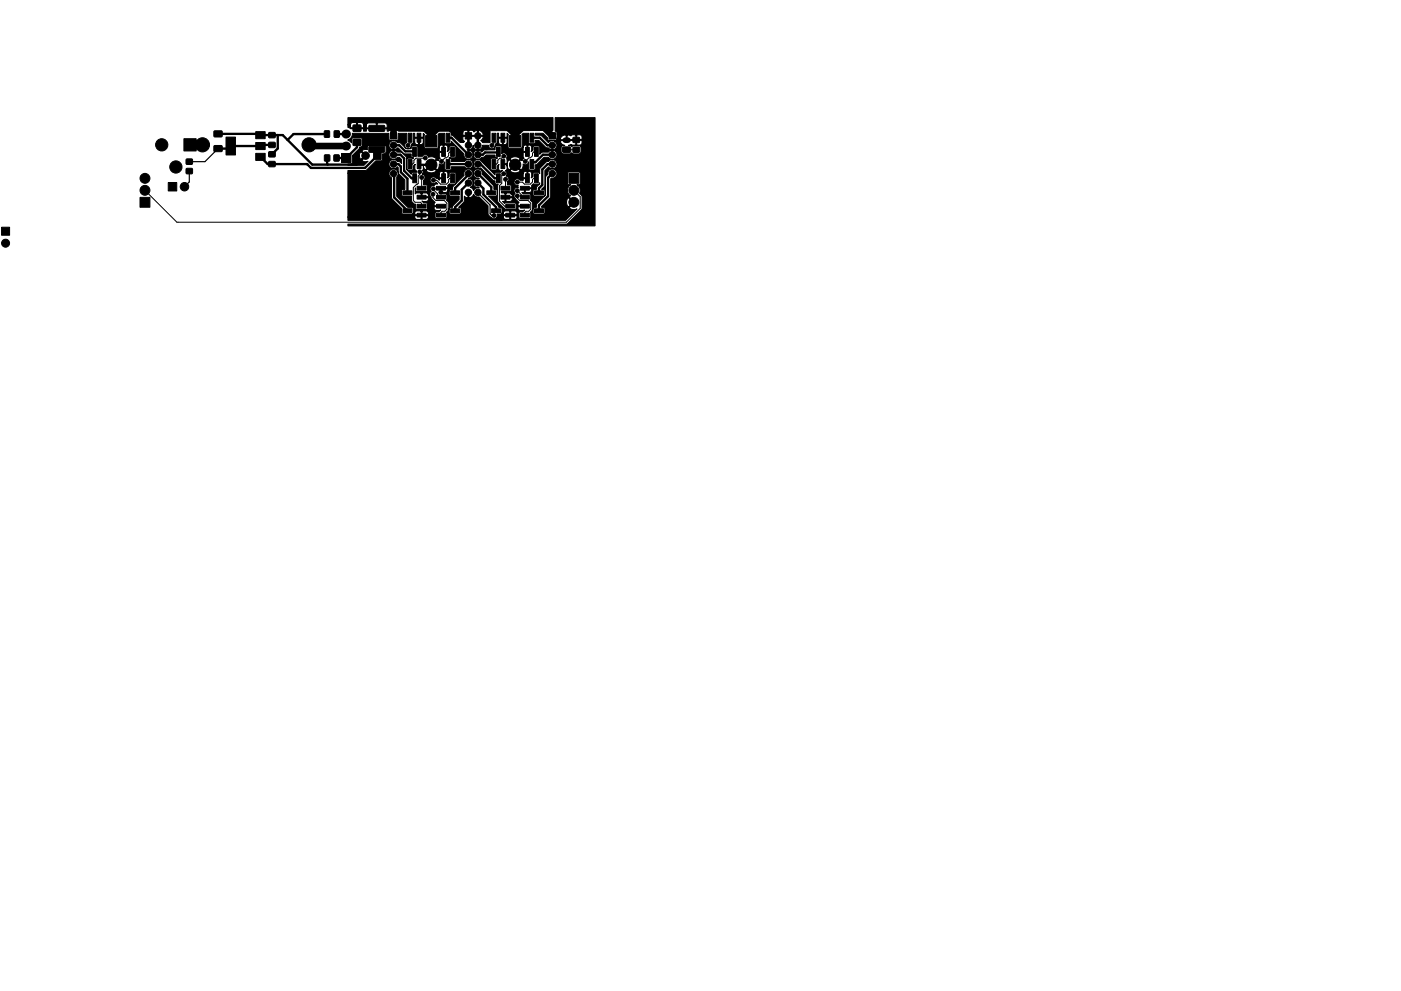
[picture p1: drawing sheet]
<svg xmlns="http://www.w3.org/2000/svg" width="297mm" height="210mm" viewBox="0 0 297 210" stroke-linecap="round" stroke-linejoin="round" font-family="sans-serif">
<g fill="#000" stroke="#000" stroke-width=".21">
<path d="M39 29.4h2.6v2.6h-2.6zM39.5 35.8h1.2l.1 1h-1.3zM39.5 33.8h1.2l.1 1h-1.3zM45.4 27.8h1.6l.1 1.2h-1.7zM45.4 30.9h1.6l.1 1.2h-1.7zM47.9 29.1h2v3.8h-2zM54.2 27.9h2v1.5h-2zM54.2 32.5h2v1.5h-2zM54.2 30.2h2v1.5h-2zM57 28.2l1.3-.1v1.1h-1.3zM57 30.2h1.3v1l-1.3 .1zM57 32.2h1.3v1l-1.3 .1z"/>
<path d="M57 34.3h1.3v1h-1.3zM68.8 27.8h1.1l-.1 1.3h-1zM68.8 32.9h1.1v1.3l-1.1-.1zM70.8 32.9h1.1v1.3l-1.1-.1zM70.9 27.8h1v1.3h-1zM72.4 32.6h2v1.9h-2zM74.9 29.5h1.6v1.3h-1.6zM74.9 26.6h1.6v1.2l-1.6 .1zM79.2 32.2h1.6v1.6h-1.6zM78.3 26.7l3.1-.1 .2 .2v.9l-.3 .2h-2.9l-.2-.2zM78.3 31.1l3.1-.1 .2 .2v1l-.3 .1h-2.9l-.2-.2zM82.8 28.1h1.3v1.4h-1.3z"/>
<path d="M86.5 28.3h.8v1.9h-.8zM86.6 33.9h.8v1.9h-.8zM87.5 31.3h.8v1.9h-.8zM87.5 36.9h.8v1.9h-.8zM88.4 28.3h.8v1.9h-.8zM88.5 33.9h.8v1.9h-.8zM88.8 34.7h.2v.2h-.3zM90.2 28.8h2.4v2.4h-2.4zM88.4 39.5h1.9v.8h-1.9zM93.6 31.3h.8v1.9h-.8zM93.6 36.9h.8v1.9h-.8zM94.6 28.3h.8v1.9h-.8z"/>
<path d="M94.6 33.9h.8v1.9h-.8zM95.5 31.3h.8v1.9h-.8zM95.5 36.9h.8v1.9h-.8zM98.6 28.1h1.4v1.4h-1.4zM104.3 28.3h.8v1.9h-.8zM104.3 33.9h.8v1.9h-.8zM105.3 31.3h.8v1.9h-.8zM105.3 36.9h.8v1.9h-.8zM106.2 28.3h.8v1.9h-.8zM106.2 33.9h.8v1.9h-.8zM108 28.8h2.4v2.4h-2.4zM106.2 39.5h1.9v.8h-1.9z"/>
<path d="M111.4 31.3h.8v1.9h-.8zM111.4 36.9h.8v1.9h-.8zM112.4 28.3h.8v1.9h-.8zM112.4 33.9h.8v1.9h-.8zM113.3 31.3h.8v1.9h-.8zM113.3 36.9h.8v1.9h-.8zM73.8 25h43.4v2.7h-13.2l-.1 2.6h-1.6l-.4-.5 .4-.4 .2-.3-.1-.2h-1v1.4h-.2v-1.4h-1.8v1.3h-.2v-1.3h-.9l-.2 .7 .4 .4-.2 .2h-.7l-1.5-1.4-.4-.1v-.6h2.4l.2 .6h.9v-.9h.2v.9h1.8v-.9h.2v.9h1a.85 .85 0 0 0-1.2-.9l-.2-.1-.5 .3-.4-.3-.9 .1-.6-.2-.3 .2-.2 .3h-2.4l-.5-.3h-10.7l-.4-.2h-.4l-.2 .2-.7-.2-.7 .2-.1-.5h-4.2l-.1 .5h-.6l-.2-.5-2.5 .1-.6-.4v-.5h.5l.1 .6h1.2v-1h.2v1h1.1l.2-.5h.6l.1 .5h2v-.9h.2v.9h2l.1-.6-.4-.4-1.9 .1-.1-.1h-1.5l-.4 .1-.1 .4h-.6l-.1-.4-.3-.2-1.1 .1-.8-.1-.3 .1-.2 .4h-.5zM116.4 28.1h1.4v1.4h-1.4zM120.6 36.8h2.1v2.1h-2.1zM119.3 31.2h1.6l.1 1-1.6 .1zM121.5 31.3l1.3-.1v1.1h-1.3zM121.5 29.2h1.3v1h-1.3z"/>
<path d="M.3 48.2h1.7v1.7h-1.7zM29.7 41.9h2.1v2.1h-2.1zM35.7 38.7h1.8v1.8h-1.8zM85.4 44.3h1.9v.8h-1.9zM85.4 40.5h1.9v.8h-1.9zM88.4 45.2h1.9v.8h-1.9zM88.4 43.3h1.9v.8h-1.9zM88.4 41.4h1.9v.8h-1.9zM92.5 43.3h1.9v.8h-1.9zM92.5 45.2h1.9v.8h-1.9zM92.5 39.5h1.9v.8h-1.9zM92.5 41.4h1.9v.8h-1.9z"/>
<path d="M95.5 44.3h1.9v.8h-1.9zM95.5 40.5h1.9v.8h-1.9zM103.2 40.5h1.9v.8h-1.9zM104.2 44.3h1.9v.8h-1.9zM106.2 41.4h1.9v.8h-1.9zM107.2 45.2h1.9v.8h-1.9zM107.2 43.3h1.9v.8h-1.9zM110.3 43.3h1.9v.8h-1.9zM110.3 45.2h1.9v.8h-1.9zM110.3 39.5h1.9v.8h-1.9zM110.3 41.4h1.9v.8h-1.9zM113.3 44.3h1.9v.8h-1.9z"/>
<path d="M113.3 40.5h1.9v.8h-1.9zM74.7 28.3h7.7l.1 1.4 .9 .1 1-.1v-1.4h1.8v1.9a.71 .71 0 0 0-.3 .9 .71 .71 0 0 0 .8 .4 .71 .71 0 0 0 .5-.8l.4-.5h.3l.1 .2a.48 .48 0 0 0 .7 .2v-1.3h.2v1.3l.2 .1a.54 .54 0 0 0 .6-.5l-.1-.9h-1.5l-.2 .9h-.3v-1.9h.3l.2 .8h1.5l.1-.8 .3 .3-.1 2.6 .2 .2 2.5 .1 .5-.2v.7l.8 .1v-1.2l-.1-.1a.54 .54 0 0 0-.7 .5h-.2v-2.7l.2-.3h1.2l.1 2.1 1.1 .1 .2-.5 2.7 2.6a.98 .98 0 0 0 .9 1.2 .98 .98 0 0 0 1-1.1 1.1 1.1 0 0 0 .9 1.1l.6-.1 .3-.3 .5-.1 .5-.4h1.9l.1 .5 .4 .1-.2 .2-1-.1-.2 .1-.1 2.1 .3 .3 .9-.1 .2-.2v-.6l.4-.3-.1 .1v1a.48 .48 0 0 0 .8 .1l-.4 .5h-1l-.1 .5-2.7-2.7a.99 .99 0 0 0-1.4-.5 .99 .99 0 0 0-.4 1.4 .99 .99 0 0 0 1.4 .3l2.6 2.6 .5 .2 .1 .6 .5 .1-.1 .3v3.3l.1 .2 1.5 1.5h2.2l.1-.3-.1-1-2.1-.1-.2 .2-.4-.5 .5-.1v-.7h.2l.1 .8h.9a.48 .48 0 0 0 .2-.8h-1.5l.1-.8h.2v.6h1.2l.1-.1a.54 .54 0 0 0-.5-.7l-1 .2-.8-.2v-.3h2l.1-.2v-1l-.2-.2h-.6v-.6h1.4v.1a.7 .7 0 0 0 .9 .6v.5a.7 .7 0 0 0-.8 .3 .7 .7 0 0 0 .1 .9 .84 .84 0 0 0 .2 1.3l.7 .6-.3 .4 .2 .3h1.4v.3l-1.4-.1a.48 .48 0 0 0-.1 .6 .48 .48 0 0 0 .4 .3l.9-.2-.3 .4-.8 .2v1.2h2.2l.2-.2-.1-1.1 .5-.4v-.3l.1 .9 .2 .2 2.2-.1 .1-1.1-.2-.2h-.5v-.2l.9-.8h4.4a.88 .88 0 0 0 .5 .9l.9-1-.9-.9a.96 .96 0 0 0-.5 1h-4.4l1-1.3 .1-3.8 .2-.1a.98 .98 0 0 0 1.1-1 .98 .98 0 0 0-1.1-.9 .98 .98 0 0 0-.9 1.1l-.4 .6v3.8l-1.9 1.8-.1 .8h-.5l-.2 .3-.1-1.3-.5-.5 .1-1.2-.3-.2h-1.3l-.3-.3 .6-.1v-.7h.2l.1 .8h.8a.48 .48 0 0 0 .3-.8h-1.4v-.2h1.4l.1-.4 .4-.4 1.1 .1 .2-.3v.2l-.6 .7-.1 .5h-.4l-.3 .2v1l.3 .2h1.9l.3-.1v-1.1l-.2-.2h-.5l.7-.9v-3.1l.8-.8a.98 .98 0 0 0 1.5 .1 .98 .98 0 0 0-.1-1.4 .98 .98 0 0 0-1.4 .2l-.5 .1-1.3 1.2-.1 1.3-.2-.3h-1l-.2 .2v.6l-.4 .3 .1-.1v-.8a.48 .48 0 0 0-.8-.3v1.4h-.8l-.2 .4-.6-.1a.7 .7 0 0 0-.8-.2 .7 .7 0 0 0-.5 .6h-1.4l.1-.1a.7 .7 0 0 0-.4-1.1l.2-.5h3.4v.7l.8 .1v-1.2a.48 .48 0 0 0-.5-.1 .48 .48 0 0 0-.3 .5h-3.4l-.4-.7h.2h.9l.4 .4 .7 .1 .6-.2 .4-.3-1.1-1.1-1 1.1h-.9l.2-.3v-.9a1.02 1.02 0 0 0 .5 1l1.1-1h.3l1 1 .4-.4 .1-.8a.7 .7 0 0 0 1.2-.5v1.6l1.1 .2 .3-.3v-.8l.4-.2 1.5-1.4h.9a.98 .98 0 0 0 1.5 .1 .98 .98 0 0 0-.1-1.4 .98 .98 0 0 0-1.4 .2h-1.3l-.6 .4-.1-1.6-1.1-.1-.2 .9-.4 .2 .1-.1v-.8a.48 .48 0 0 0-.8-.3v1.4h-.8l-.2 .9a.43 .43 0 0 1-.1 .7l-.1 .2-.3-.2-1 1.1h-.3l-1.1-1.1-.4 .4-.1 .7-1-.1v-.2h.9l.1-.1v-.8h.7l1 1 1.1-1a1.31 1.31 0 0 0-2.1 0h-.7l-.1-.2a.74 .74 0 0 0-.1-.9 .74 .74 0 0 0-.9-.1v-1.4l-.3-.2h-1l-.1 .8h-2.3l-.6 .5a1.02 1.02 0 0 0-1-.4 1.02 1.02 0 0 0-.8 .8 .97 .97 0 0 0-1.2-.8l-.1-.1a1.04 1.04 0 0 0 1.3-1 .98 .98 0 0 0 1 1 .98 .98 0 0 0 1-1h1.3v.1a.75 .75 0 0 0 .9 .6 .75 .75 0 0 0 .5-.9l.4-.4 .3 .1a.48 .48 0 0 0 .8 .3v-1.3h.2v1.3l.1 .1a.54 .54 0 0 0 .7-.5l-.1-.9h-1.6l-.1 .9h-.3v-1.9h.3l.1 .8h1.6l.1-.8 .3 .3-.1 2.6 .2 .2 2.5 .1 .5-.2v.7l.8 .1v-1.2a.48 .48 0 0 0-.5-.1 .48 .48 0 0 0-.3 .5h-.2l-.1-2.7 .3-.3h1.2v1.9l.1 .2 1.1 .1 .2-.3v-.4h.7l1.5 1.5 .6 .1a.98 .98 0 0 0 1.5 .1 .98 .98 0 0 0-.2-1.5h1.2l.4 .6 .6 .2a.61 .61 0 0 0-.8 .6v.9l.5 .3h1.4l.3-.2 .4 .2h1.3l.3-.4v-.8a.55 .55 0 0 0-.6-.5h-1l-.4 .2-.2-.2-.5-.1 .6-.2 .8 .2 .2-.1v-.9h.2v.9l.1 .1 .7-.1 .3-.3-.1-.6-5.7 .2a1 1 0 0 0-1.3 .3l-1.5-1.5-1.3-.1v-.4h1.6l1 1v.3l.3 .2h1.4l.3-.3 1.9 .1v-1h.2v1h1.9v-.9h.2v.9h1l.1-.1v-.6l-.4-.3-.7 .1-.9-.1-.4 .2-.3-.1a1.44 1.44 0 0 0-1.9 .8h-.7v-1.4l-.4-.3v-2.8h8.5v22.9h-52.4v-.4h46.4l3.2-3.2v-2.6l-.5-.7 .1-.8-.1-.5-.6-.5h.5l.2-.3v-2.1l-.1-.3h-2.3l-.2 .1-.1 2.3 .2 .3h.5a1.35 1.35 0 0 0 0 2.3l-.3 .3 1.1 1.1-1.1 1.1a1.23 1.23 0 0 0 1.6 .3l-2.4 2.4h-46.1v-.7h14.1l.3 .5h1l.1-.8h.2l.1 .8h.8a.48 .48 0 0 0 .3-.8h-2.6l-.2 .3h-14.1v-9.3h8.7l.1 .6 .4 .4 .1 4.4 2 2.1 .1 1.1 2.1 .1 .6-.2 .2 .3h1.2v-.6h.2v.6h1.2a.48 .48 0 0 0 .1-.5 .48 .48 0 0 0-.5-.3l-.8 .2-1.2-.1-.3 .2-.1 .2h-.3l-.1-1.1-1-.1-2.4-2.3 .1-4.3a.98 .98 0 0 0-.4-1.5 .98 .98 0 0 0-1.3 .8h-8.7v-.5l3.9-.1 2-2 1.3-.1 .1-1.4h.2a.55 .55 0 0 0 .6-.5v-.9l-.4-.4-3.1-.1a.55 .55 0 0 0-.5 .6v.5l-.7-.1-.4 .2-.1 .2 1 .9-1 .9 .1 .2 .5 .2 .7-.1-.8 .9h-3.4v-.3h.7l.2-.2v-1.5h1.5l.2 .6 .2 .1 .8-.8-.8-.7h-.2l-.2 .8h-1.5l1.4-1.5 .1-.4 .4-.1 .3-.4h5.6a.98 .98 0 0 0 .6 1 .98 .98 0 0 0 1.1-.3h.2l1.3 1.2 1.5 .1v.6l.5 .2-.1 .1h-1l-.3 .1v2.1l.2 .3 1-.1 .2-.2v-.6l.4-.3-.1 .1v.9l.3 .3v.4h-.9l-.2 .4-1-1-.1-2.7-.9-.9-1-.2a.98 .98 0 0 0-1.4-.1 .98 .98 0 0 0 0 1.5 .98 .98 0 0 0 1.4-.2h.5l.4 .4v.9l-.4-.4h-.5a.98 .98 0 0 0-1.4-.2 .98 .98 0 0 0 0 1.5 .98 .98 0 0 0 1.5-.2l.1 .1 .1 1.3 1.3 1.4v2h-.4l-.2 .2v1.1l2 .1 .1 1.1 .5 .6h.3v.9l.3 .2h2.1l.1-.3v-.9l-.8-.2-.3-.4 .1 .1h.9a.48 .48 0 0 0 .2-.8l-1.4 .1v-.9h.2v.6h1.2l.1-.1-.1-.5h.4l.4 1.1 .8 .7-.3 .6 .2 .1h1.4v.3l-1.4-.1a.48 .48 0 0 0-.1 .6 .48 .48 0 0 0 .4 .3l.9-.2-.3 .4-.8 .2-.1 .9 .2 .3h2l.3-.1v-1.2l.4-.5v-1.5l-.4-.5v-1.3l-1.5-.1-.1-.3 .3-.1v-.7h.2l.1 .8h.8l.4-.3h.3l.1 .8 .1 .3h1.9v.7l-1.2 1.3-.2 .4h-.4l-.2 .2v1l.2 .2 2.2-.1v-1.1l-.5-.2 1.2-1.2v-1.2l.6 .4 .2-.1v-1.2h.2v1.2l.2 .1 .6-.4 .2-.4a.97 .97 0 0 0 1.2 .6l1.9 1.9v1.7l.4 .6a.9 .9 0 0 0 1.5 0h1.3l.3 .5h1l.1-.8h.2l.1 .8h.9a.48 .48 0 0 0 .2-.8h-2.6l-.2 .3h-1.3v-.6l1.3-.2 .2 .3h1.2v-.6h.2v.6h1.2l.1-.1a.54 .54 0 0 0-.5-.7l-.8 .2-1.2-.1-.3 .2-.1 .2h-.3v-1.1l-.7-.1-.1-.4-2-2 1.7-.1 .1-.2v-.9l-.2-.2h-.5l-.1-.8-2.3-2.4a.98 .98 0 0 0-.9-1.2 .98 .98 0 0 0-1.1 1.1 .98 .98 0 0 0 1.2 .9l.1 .1a.98 .98 0 0 0-1.3 .9 .98 .98 0 0 0 1.2 1l.1 .1a.97 .97 0 0 0-1.2 .5l-.2-.4-.5-.3a.97 .97 0 0 0 .6-1.1 .97 .97 0 0 0-1-.8 .99 .99 0 0 0 1-1 .99 .99 0 0 0-1.2-.9 .99 .99 0 0 0-.7 1.3l-2.3 2.3-.2 .7h-.4l-.3 .3h-.3l-.1-.5h-1.4v-.2h1.4l.1-.4 .4-.4 1.1 .1 .2-.3v-2.1l-1.2-.1-.2 .8-.4 .3 .1-.1v-.8a.48 .48 0 0 0-.8-.3v1.4h-.8l-.2 .3-.5-.4a.76 .76 0 0 0-1-.2 .76 .76 0 0 0-.2 1.1 .7 .7 0 0 0 1.1 0l.3 .3-.4 .1-.4 .2a.7 .7 0 0 0-.7 .5 .7 .7 0 0 0 .2 .8l-.4 .5-.8-.2-.8 .2-1.1-.2-.4 .2 .1-1.2 .1 .6 .2 .1h1.9l.3-.1v-1.1l-.2-.2h-.6v-1a.7 .7 0 0 0 .3-.7 .7 .7 0 0 0-.6-.5l3.6-.1v.7l.8 .1v-1.2l-.1-.1a.54 .54 0 0 0-.7 .5h-3.5v-.7h.8a1.31 1.31 0 0 0 2.1 0l-1.1-1.1-1 1.1h-.8l.2-1 .2 .7 .3 .1 1-1h.3l1 1 .4-.4 .1-.8a.7 .7 0 0 0 1.2-.5v1.5l.2 .3 1.1-.1 .1-.6h2.8a.98 .98 0 0 0 1.5 .2 .98 .98 0 0 0 0-1.5 .98 .98 0 0 0-1.5 .2h-2.8l-.1-.6-.4-.1 .1-.2 1 .1 .3-.2v-2.1l-.2-.2h-1l-.1 .2-.1 .7-.4 .2 .1-.1v-.8a.48 .48 0 0 0-.8-.3l.1 1.4h-.9l-.2 .9a.43 .43 0 0 1-.1 .7l-.1 .2-.3-.2-1 1.1h-.3l1.2-1.2a1.34 1.34 0 0 0-1.6-.4 .7 .7 0 0 0-.6-.6 .7 .7 0 0 0-.7 .4h-1v-1.9l-.1-.3h-1.1l-.2 .2v.4h-1l-1.3-1.2-.7-.1a.98 .98 0 0 0-1-.4 .98 .98 0 0 0-.7 .8h-5.6v-1.1l-.2-.3-.4-.1h-1.2a.55 .55 0 0 0-.6 .5v.6l-.7-.5a1.54 1.54 0 0 0 .9-1.5z"/>
<circle cx="30.7" cy="37.8" r="1.05"/>
<circle cx="34.3" cy="30.7" r="1.3"/>
<circle cx="37.3" cy="35.4" r="1.3"/>
<circle cx="39.1" cy="39.6" r=".9"/>
<circle cx="42.9" cy="30.7" r="1.5"/>
<circle cx="65.5" cy="30.7" r="1.5"/>
<circle cx="77.5" cy="33" r=".8"/>
<circle cx="79.6" cy="37.8" r=".4"/>
<circle cx="83.4" cy="30.8" r=".67"/>
<circle cx="83.4" cy="32.8" r=".67"/>
<circle cx="83.4" cy="34.8" r=".67"/>
<circle cx="83.4" cy="36.8" r=".67"/>
<circle cx="85.5" cy="30" r=".4"/>
<circle cx="86.5" cy="30.9" r=".4"/>
<circle cx="89" cy="36.4" r=".4"/>
<circle cx="89.4" cy="37.6" r=".4"/>
<circle cx="90.2" cy="33.5" r=".4"/>
<circle cx="91.4" cy="35" r="1.2"/>
<circle cx="91.9" cy="38.2" r=".4"/>
<circle cx="93.6" cy="34.2" r=".4"/>
<circle cx="99.3" cy="30.8" r=".67"/>
<circle cx="99.3" cy="32.8" r=".67"/>
<circle cx="99.3" cy="34.8" r=".67"/>
<circle cx="99.3" cy="38.8" r=".67"/>
<circle cx="99.3" cy="36.8" r=".67"/>
<circle cx="101.3" cy="30.8" r=".67"/>
<circle cx="101.3" cy="28.8" r=".67"/>
<circle cx="101.3" cy="32.8" r=".67"/>
<circle cx="101.3" cy="34.8" r=".67"/>
<circle cx="101.3" cy="38.8" r=".67"/>
<circle cx="101.3" cy="36.8" r=".67"/>
<circle cx="103.1" cy="31.4" r=".4"/>
<circle cx="104.3" cy="30.9" r=".4"/>
<circle cx="106.8" cy="36.8" r=".4"/>
<circle cx="106.8" cy="33.1" r=".4"/>
<circle cx="107.2" cy="38" r=".4"/>
<circle cx="109.2" cy="35" r="1.2"/>
<circle cx="109.7" cy="38.6" r=".4"/>
<circle cx="111.4" cy="34.2" r=".4"/>
<circle cx="117.1" cy="30.8" r=".67"/>
<circle cx="117.1" cy="32.8" r=".67"/>
<circle cx="117.1" cy="34.8" r=".67"/>
<circle cx="117.1" cy="36.8" r=".67"/>
<circle cx="1.2" cy="51.6" r=".85"/>
<circle cx="30.7" cy="40.4" r="1.05"/>
<circle cx="79.6" cy="43.4" r=".4"/>
<circle cx="91.8" cy="41.2" r=".4"/>
<circle cx="91.9" cy="40" r=".4"/>
<circle cx="93.5" cy="40.8" r=".4"/>
<circle cx="99.3" cy="40.8" r=".67"/>
<circle cx="101.3" cy="40.8" r=".67"/>
<circle cx="104.8" cy="45.7" r=".4"/>
<circle cx="106.3" cy="46.3" r=".4"/>
<circle cx="108.6" cy="40.9" r=".4"/>
<circle cx="109.7" cy="41.5" r=".4"/>
<circle cx="109.7" cy="40.4" r=".4"/>
<circle cx="121.7" cy="42.9" r="1.05"/>
<circle cx="121.7" cy="40.4" r="1.05"/>
</g>
<path d="M73.4 28.4h.1M73.4 31h.1" fill="none" stroke="#000" stroke-width="1.9"/>
<path d="M119.9 29.7h.5" fill="none" stroke="#000" stroke-width="1.2"/>
<path d="M65.5 30.7l.3 .3h7.6M83.4 27.3v1.5M90 27.2l1.4 1.4M91.4 28.6v1.4M92.8 27.2l-1.4 1.4M107.8 27.2l1.4 1.4M109.2 28.6v1.4M110.6 27.2l-1.4 1.4M114.7 26.4l2.4 2.4" fill="none" stroke="#000" stroke-width="1.4"/>
<g fill="none" stroke="#000" stroke-width=".5">
<path d="M46.2 28.4h8.7l.3 .3M55.2 28.7h.1M55.2 28.7h4.7l6.3 6.2h9.4l1.9-1.9M57.7 30.7h-2.2l-.3 .3h-6.3l-.5 .5h-2.2M58.9 28.7v2.8l-1.2 1.2M69.3 28.4h-7.1l-1.2 1.3M69.4 33.5l.1 1.4M71.4 28.4h2M75.7 30.2v1l-2.3 2.3h-2M80 31.7v1.3l-2.6 2.6h-11.5l-.8-.8h-8.3l-1.6-1.5M83.4 32.8h1.5l.8 .8v2.6l1.6 1.6h.6M83.6 34.8h.9l.5 .5v1.2l1.4 1.4v3h-.7"/>
<path d="M83.6 36.8v5.1l2.8 2.8M83.6 30.8h1l1.3 1.3h1.9l.1 .8M88.9 34.8l.1 .2h2.6M93.1 39.9h.4M95 29.2h.7l3.6 3.6M95 34.8h.1M95 34.8h4.3M99.3 28.8v2M99.3 36.8v.3l-2.8 2.8v1M99.3 38.8l-1.4 1.4v2.4l-1.4 1.4v.7M101.3 36.8l2.9 2.9v1.2h-.7M101.3 28.8v2"/>
<path d="M101.3 38.8l1.2 1.2v1.3l2.7 2.7v.7M101.3 34.8h.6l3 3h.8M105.7 32.2l-.2 .1h-2.7l-.4 .5h-1.1M109.2 35h.1M111 39.9h.3M112.8 29.2h1.7l1.5 1.6h1.1M117.1 34.8h-1l-1.1 1.2v3.2l-.7 .7v1M117.1 36.8l-.9 .9v3.9l-1.9 2v1.1M117.1 32.8h-2l-1.6 1.6h-.7v.4"/>
</g>
<g fill="none" stroke="#000" stroke-width=".21">
<path d="M86.7 29.5l.2-.3v1.2l-.4 .5M88.8 29.2v.5M89 36.4v.6l-.3 .3v1.6l-1.1 .9v2.7l.4 .4h1.2l.2 .3v.5M89.4 38v1.9M90.2 33.5l-2 .1-.4 .4v.5l-.3 .3h-.6M95.9 37.8h-.5l-.3 .3v.5l-.4 .5h-1.3l-.8-.9h-.7M95.9 32.2h-.5l-.3 .3v.5l-.4 .5h-.3l-.8 .7M95.9 37.8h.1M104.5 29.5l.2-.3v1.2l-.4 .5M106.6 29.2v.5M106.8 36.8l-.4 .4v1.7l-.5 .5v3.3l1.1 1h1.2M106.8 33.1l-.4 .5h-.4l-.5 .4v.5l-.2 .3h-.6"/>
<path d="M107.2 38v1.9M107.2 39.9h.1M113.7 37.8h-.5l-.3 .3v.5l-.5 .5h-1.2l-.4-.5h-1.1M113.7 32.2h-.5l-.3 .3v.5l-.4 .5h-.4l-.7 .7M113.7 37.8h.1M120.1 31.7l.1 .1M120.2 31.8h2M122.2 29.7h-2.1M30.7 40.4l6.8 6.7h82.6l2.9-2.9v-2.5l-1.3-1.3M91.8 41.2v.7l.6 .6h1.8l.5 .6v1.3l-.4 .4h-.6l-.2 .3v.5M91.9 40v.3l.9 .8v.3l.4 .4M92.7 41.8h.8"/>
<path d="M101.3 40.8v.1M108 45.6h.2M109.7 41.5v.5l.5 .5h1.8l.5 .6v1.3l-.4 .4h-.6l-.2 .3v.5M109.8 40.4l.7 .9 .1 .5h.7"/>
</g>
<path d="M40.1 36.3v2.3l-1 1M46.2 31.5l-2.7 2.8h-3.4M101.3 40.8l2.6 2.7v1.9l.4 .3h.5" fill="none" stroke="#000" stroke-width=".25"/>
<path d="M40.3 30.7h2.6" fill="none" stroke="#000" stroke-width="2"/>
</svg>
